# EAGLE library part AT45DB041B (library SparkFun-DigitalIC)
4-Mbit SPI flash memory

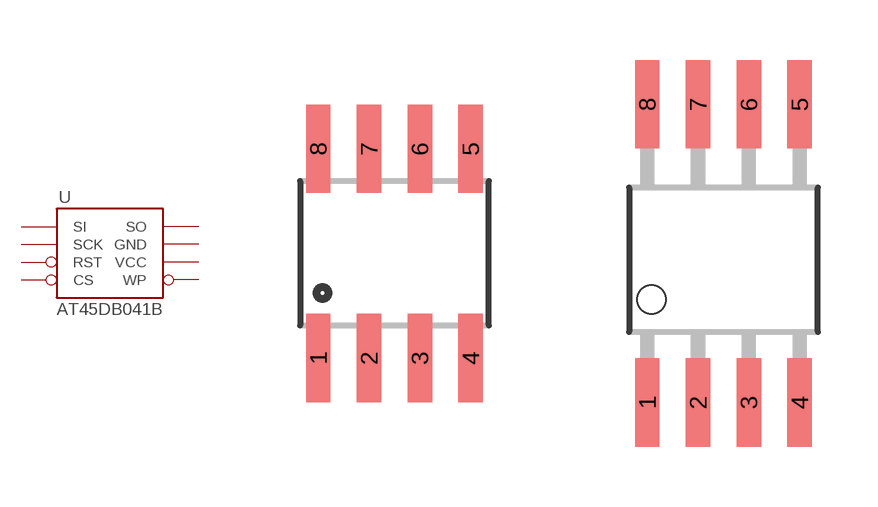
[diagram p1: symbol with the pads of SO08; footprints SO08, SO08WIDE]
Designator prefix -

## AT45DB041B  [SO08]
1  SI
2  SCK
3  RST
4  CS
5  WP
6  VCC
7  GND
8  SO

## AT45DB041BWIDE  [SO08WIDE]
Pads as for SO08

## Footprint SO08 (pad centres in mm)
Small Outline Package Fits JEDEC packages (narrow SOIC-8)
smd 0.61 x 2.21: 1 -1.905,-2.616; 2 -0.635,-2.616; 3 0.635,-2.616; 4 1.905,-2.616; 5 1.905,2.616; 6 0.635,2.616; 7 -0.635,2.616; 8 -1.905,2.616

## Footprint SO08WIDE (pad centres in mm)
smd 0.61 x 2.21: 1 -1.905,-3.569; 2 -0.635,-3.569; 3 0.635,-3.569; 4 1.905,-3.569; 5 1.905,3.886; 6 0.635,3.886; 7 -0.635,3.886; 8 -1.905,3.886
